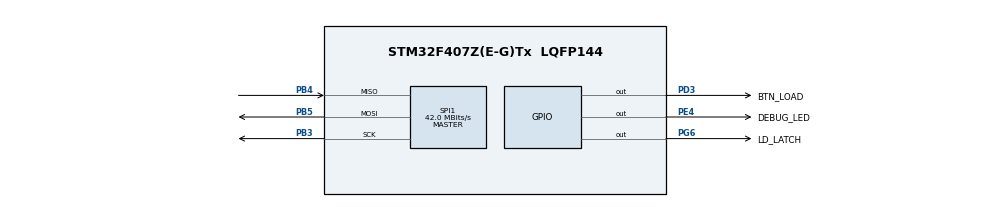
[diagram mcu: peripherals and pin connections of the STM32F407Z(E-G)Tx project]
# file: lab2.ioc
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Mcu.Family=STM32F4
Mcu.Name=STM32F407Z(E-G)Tx
Mcu.Package=LQFP144
NVIC.PriorityGroup=NVIC_PRIORITYGROUP_4
NVIC.TIM2_IRQn=true\:0\:0\:false\:false\:true\:true\:true\:true
PA13.Mode=Serial_Wire
PA13.Signal=SYS_JTMS-SWDIO
PA14.Mode=Serial_Wire
PA14.Signal=SYS_JTCK-SWCLK
PB3.Mode=Full_Duplex_Master
PB3.Signal=SPI1_SCK
PB4.Mode=Full_Duplex_Master
PB4.Signal=SPI1_MISO
PB5.Mode=Full_Duplex_Master
PB5.Signal=SPI1_MOSI
PD3.GPIO_Label=BTN_LOAD
PD3.Signal=GPIO_Output
PE4.GPIO_Label=DEBUG_LED
PE4.Signal=GPIO_Output
PG6.GPIO_Label=LD_LATCH
PG6.Signal=GPIO_Output
PH0-OSC_IN.Mode=HSE-External-Oscillator
PH0-OSC_IN.Signal=RCC_OSC_IN
PH1-OSC_OUT.Mode=HSE-External-Oscillator
PH1-OSC_OUT.Signal=RCC_OSC_OUT
ProjectManager.HeapSize=0x200
ProjectManager.StackSize=0x400
ProjectManager.TargetToolchain=STM32CubeIDE
RCC.48MHZClocksFreq_Value=84000000
RCC.AHBFreq_Value=168000000
RCC.APB1CLKDivider=RCC_HCLK_DIV4
RCC.APB1Freq_Value=42000000
RCC.APB1TimFreq_Value=84000000
RCC.APB2CLKDivider=RCC_HCLK_DIV2
RCC.APB2Freq_Value=84000000
RCC.APB2TimFreq_Value=168000000
RCC.CortexFreq_Value=168000000
RCC.HCLKFreq_Value=168000000
RCC.HSE_VALUE=25000000
RCC.HSI_VALUE=16000000
RCC.LSE_VALUE=32768
RCC.PLLM=8
RCC.PLLN=168
RCC.SYSCLKFreq_VALUE=168000000
RCC.SYSCLKSource=RCC_SYSCLKSOURCE_PLLCLK
RCC.VCOOutputFreq_Value=336000000
SPI1.CalculateBaudRate=42.0 MBits/s
SPI1.Direction=SPI_DIRECTION_2LINES
SPI1.Mode=SPI_MODE_MASTER
SPI1.VirtualType=VM_MASTER
TIM2.Period=10-1
TIM2.Prescaler=8400-1
VP_TIM2_VS_ClockSourceINT.Mode=Internal
board=custom

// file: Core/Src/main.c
/* USER CODE BEGIN Header */
/**
  ******************************************************************************
  * @file           : main.c
  * @brief          : Main program body
  ******************************************************************************
  * @attention
  *
  * Copyright (c) 2024 STMicroelectronics.
  * All rights reserved.
  *
  * This software is licensed under terms that can be found in the LICENSE file
  * in the root directory of this software component.
  * If no LICENSE file comes with this software, it is provided AS-IS.
  *
  ******************************************************************************
  */
/* USER CODE END Header */
#include "main.h"
#include "spi.h"
#include "tim.h"
#include "gpio.h"

/* USER CODE BEGIN Includes */
#include "softwareTimer.h"
#include "led7Seg.h"
#include "clock.h"
#include "button.h"
/* USER CODE END Includes */

void SystemClock_Config(void);

/* USER CODE BEGIN 0 */

void initSystem(void);
void debugProgram(void);

/* USER CODE END 0 */

int main(void)
{

  /* MCU Configuration--------------------------------------------------------*/

  /* Reset of all peripherals, Initializes the Flash interface and the Systick. */
  HAL_Init();

  /* Configure the system clock */
  SystemClock_Config();

  /* Initialize all configured peripherals */
  MX_GPIO_Init();
  MX_TIM2_Init();
  MX_SPI1_Init();
  /* USER CODE BEGIN 2 */

  initSystem();
  initClock(10, 10);

  /* USER CODE END 2 */

  /* Infinite loop */
  /* USER CODE BEGIN WHILE */
  while (1)
  {
	  if(getFlagTimer2())
	  {
		  setTimer2(50);

		  clockFSM();

		  button_scan();
	  }
    /* USER CODE END WHILE */

  }
}

void SystemClock_Config(void)
{
  RCC_OscInitTypeDef RCC_OscInitStruct = {0};
  RCC_ClkInitTypeDef RCC_ClkInitStruct = {0};

  /** Configure the main internal regulator output voltage
  */
  __HAL_RCC_PWR_CLK_ENABLE();
  __HAL_PWR_VOLTAGESCALING_CONFIG(PWR_REGULATOR_VOLTAGE_SCALE1);

  /** Initializes the RCC Oscillators according to the specified parameters
  * in the RCC_OscInitTypeDef structure.
  */
  RCC_OscInitStruct.OscillatorType = RCC_OSCILLATORTYPE_HSI;
  RCC_OscInitStruct.HSIState = RCC_HSI_ON;
  RCC_OscInitStruct.HSICalibrationValue = RCC_HSICALIBRATION_DEFAULT;
  RCC_OscInitStruct.PLL.PLLState = RCC_PLL_ON;
  RCC_OscInitStruct.PLL.PLLSource = RCC_PLLSOURCE_HSI;
  RCC_OscInitStruct.PLL.PLLM = 8;
  RCC_OscInitStruct.PLL.PLLN = 168;
  RCC_OscInitStruct.PLL.PLLP = RCC_PLLP_DIV2;
  RCC_OscInitStruct.PLL.PLLQ = 4;
  if (HAL_RCC_OscConfig(&RCC_OscInitStruct) != HAL_OK)
  {
    Error_Handler();
  }

  /** Initializes the CPU, AHB and APB buses clocks
  */
  RCC_ClkInitStruct.ClockType = RCC_CLOCKTYPE_HCLK|RCC_CLOCKTYPE_SYSCLK
                              |RCC_CLOCKTYPE_PCLK1|RCC_CLOCKTYPE_PCLK2;
  RCC_ClkInitStruct.SYSCLKSource = RCC_SYSCLKSOURCE_PLLCLK;
  RCC_ClkInitStruct.AHBCLKDivider = RCC_SYSCLK_DIV1;
  RCC_ClkInitStruct.APB1CLKDivider = RCC_HCLK_DIV4;
  RCC_ClkInitStruct.APB2CLKDivider = RCC_HCLK_DIV4;

  if (HAL_RCC_ClockConfig(&RCC_ClkInitStruct, FLASH_LATENCY_5) != HAL_OK)
  {
    Error_Handler();
  }
}

/* USER CODE BEGIN 4 */
void initSystem()
{
	initializeTimer2();
	led_7seg_init();
	setTimer2(1000);
}
void debugProgram()
{
	HAL_GPIO_TogglePin(GPIOE, DEBUG_LED_Pin);
}
/* USER CODE END 4 */

void Error_Handler(void)
{
  __disable_irq();
  while (1)
  {
  }
}
